VERSION 5.8 ;
BUSBITCHARS "[]" ;
DIVIDERCHAR "/" ;

SITE  CoreSite2
    CLASS       CORE ;
    SYMMETRY    Y ;
    SIZE        0.48 BY 7.56 ;
END  CoreSite2

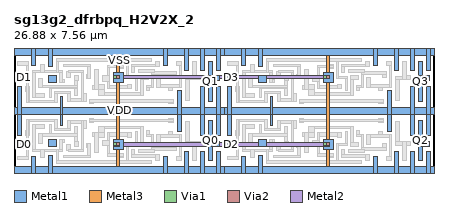
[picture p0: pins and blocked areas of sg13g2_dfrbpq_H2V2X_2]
MACRO sg13g2_dfrbpq_H2V2X_2
  CLASS CORE ;
  ORIGIN 0 0 ;
  FOREIGN sg13g2_dfrbpq_H2V2X_2 0 0 ;
  SIZE 26.880 BY 7.560 ;
  SYMMETRY X Y ;
  SITE CoreSite2 ;
  PIN D0
    DIRECTION INPUT ;
    USE SIGNAL ;
    ANTENNAMODEL OXIDE1 ;
    ANTENNAGATEAREA 0.1092 LAYER Metal1 ;
    PORT
      LAYER Metal1 ;
        RECT 0.255 1.375 0.610 1.855 ;
    END
  END D0
  PIN Q0
    DIRECTION OUTPUT ;
    USE SIGNAL ;
    ANTENNADIFFAREA 0.7161 LAYER Metal1 ;
    PORT
      LAYER Metal1 ;
        RECT 12.440 1.505 13.150 1.845 ;
        RECT 12.440 0.595 12.700 3.160 ;
    END
  END Q0
  PIN D1
    DIRECTION INPUT ;
    USE SIGNAL ;
    ANTENNAMODEL OXIDE1 ;
    ANTENNAGATEAREA 0.1092 LAYER Metal1 ;
    PORT
      LAYER Metal1 ;
        RECT 0.255 5.705 0.610 6.185 ;
    END
  END D1
  PIN Q1
    DIRECTION OUTPUT ;
    USE SIGNAL ;
    ANTENNADIFFAREA 0.7161 LAYER Metal1 ;
    PORT
      LAYER Metal1 ;
        RECT 12.440 4.400 12.700 6.965 ;
        RECT 12.440 5.715 13.150 6.055 ;
    END
  END Q1
  PIN D2
    DIRECTION INPUT ;
    USE SIGNAL ;
    ANTENNAMODEL OXIDE1 ;
    ANTENNAGATEAREA 0.1092 LAYER Metal1 ;
    PORT
      LAYER Metal1 ;
        RECT 13.695 1.375 14.050 1.855 ;
    END
  END D2
  PIN Q2
    DIRECTION OUTPUT ;
    USE SIGNAL ;
    ANTENNADIFFAREA 0.7161 LAYER Metal1 ;
    PORT
      LAYER Metal1 ;
        RECT 25.880 1.505 26.590 1.845 ;
        RECT 25.880 0.595 26.140 3.160 ;
    END
  END Q2
  PIN D3
    DIRECTION INPUT ;
    USE SIGNAL ;
    ANTENNAMODEL OXIDE1 ;
    ANTENNAGATEAREA 0.1092 LAYER Metal1 ;
    PORT
      LAYER Metal1 ;
        RECT 13.695 5.705 14.050 6.185 ;
    END
  END D3
  PIN Q3
    DIRECTION OUTPUT ;
    USE SIGNAL ;
    ANTENNADIFFAREA 0.7161 LAYER Metal1 ;
    PORT
      LAYER Metal1 ;
        RECT 25.880 4.400 26.140 6.965 ;
        RECT 25.880 5.715 26.590 6.055 ;
    END
  END Q3
  PIN VDD
    DIRECTION INOUT ;
    USE POWER ;
    SHAPE ABUTMENT ;
    NETEXPR "VDD VDD!" ;
    PORT
      LAYER Metal1 ;
        RECT 11.930 2.190 12.190 4.000 ;
        RECT 25.370 2.190 25.630 4.000 ;
        RECT 0.215 2.215 0.470 4.000 ;
        RECT 13.655 2.215 13.910 4.000 ;
        RECT 12.955 2.220 13.215 4.000 ;
        RECT 26.395 2.220 26.655 4.000 ;
        RECT 10.450 2.460 10.710 4.000 ;
        RECT 23.890 2.460 24.150 4.000 ;
        RECT 2.945 2.860 3.115 4.000 ;
        RECT 16.385 2.860 16.555 4.000 ;
        RECT 0.000 3.560 13.440 4.000 ;
        RECT 13.440 3.560 26.880 4.000 ;
        RECT 2.945 3.560 3.115 4.700 ;
        RECT 16.385 3.560 16.555 4.700 ;
        RECT 10.450 3.560 10.710 5.100 ;
        RECT 23.890 3.560 24.150 5.100 ;
        RECT 12.955 3.560 13.215 5.340 ;
        RECT 26.395 3.560 26.655 5.340 ;
        RECT 0.215 3.560 0.470 5.345 ;
        RECT 13.655 3.560 13.910 5.345 ;
        RECT 11.930 3.560 12.190 5.370 ;
        RECT 25.370 3.560 25.630 5.370 ;
    END
  END VDD
  PIN VSS
    DIRECTION INOUT ;
    USE GROUND ;
    SHAPE ABUTMENT ;
    NETEXPR "VSS VSS!" ;
    PORT
      LAYER Metal1 ;
        RECT 0.000 -0.220 13.440 0.220 ;
        RECT 13.440 -0.220 26.880 0.220 ;
        RECT 9.560 -0.220 9.820 0.885 ;
        RECT 1.140 -0.220 1.400 0.885 ;
        RECT 23.000 -0.220 23.260 0.885 ;
        RECT 14.580 -0.220 14.840 0.885 ;
        RECT 2.235 -0.220 2.495 0.915 ;
        RECT 15.675 -0.220 15.935 0.915 ;
        RECT 10.925 -0.220 11.160 1.190 ;
        RECT 24.365 -0.220 24.600 1.190 ;
        RECT 12.960 -0.220 13.215 1.200 ;
        RECT 11.935 -0.220 12.200 1.200 ;
        RECT 26.400 -0.220 26.655 1.200 ;
        RECT 25.375 -0.220 25.640 1.200 ;
    END
    PORT
      LAYER Metal1 ;
        RECT 12.960 6.360 13.215 7.780 ;
        RECT 11.935 6.360 12.200 7.780 ;
        RECT 26.400 6.360 26.655 7.780 ;
        RECT 25.375 6.360 25.640 7.780 ;
        RECT 10.925 6.370 11.160 7.780 ;
        RECT 24.365 6.370 24.600 7.780 ;
        RECT 2.235 6.645 2.495 7.780 ;
        RECT 15.675 6.645 15.935 7.780 ;
        RECT 9.560 6.675 9.820 7.780 ;
        RECT 1.140 6.675 1.400 7.780 ;
        RECT 23.000 6.675 23.260 7.780 ;
        RECT 14.580 6.675 14.840 7.780 ;
        RECT 0.000 7.340 13.440 7.780 ;
        RECT 13.440 7.340 26.880 7.780 ;
    END
  END VSS
  PIN CLK
    DIRECTION INPUT ;
    USE SIGNAL ;
    ANTENNAMODEL OXIDE1 ;
    ANTENNAGATEAREA 0.2418 LAYER Metal1 ;
    PORT
      LAYER Metal1 ;
        RECT 6.365 1.335 6.990 1.935 ;
        RECT 6.365 5.625 6.990 6.225 ;
        RECT 19.805 1.335 20.430 1.935 ;
        RECT 19.805 5.625 20.430 6.225 ;
      LAYER Metal3 ;
        RECT 6.580 0.200 6.780 7.360 ;
      LAYER Via1 ;
        RECT 6.365 1.540 6.555 1.730 ;
      LAYER Via2 ;
        RECT 6.580 1.540 6.770 1.730 ;
      LAYER Metal2 ;
        RECT 6.360 1.535 6.775 1.735 ;
      LAYER Via1 ;
        RECT 6.365 5.830 6.555 6.020 ;
      LAYER Via2 ;
        RECT 6.580 5.830 6.770 6.020 ;
      LAYER Metal2 ;
        RECT 6.360 5.825 6.775 6.025 ;
      LAYER Metal3 ;
        RECT 20.020 0.200 20.220 7.360 ;
      LAYER Via1 ;
        RECT 19.805 1.540 19.995 1.730 ;
      LAYER Via2 ;
        RECT 20.020 1.540 20.210 1.730 ;
      LAYER Metal2 ;
        RECT 19.800 1.535 20.215 1.735 ;
      LAYER Via1 ;
        RECT 19.805 5.830 19.995 6.020 ;
      LAYER Via2 ;
        RECT 20.020 5.830 20.210 6.020 ;
      LAYER Metal2 ;
        RECT 19.800 5.825 20.215 6.025 ;
        RECT 6.360 1.535 20.215 1.735 ;
        RECT 6.360 5.825 20.215 6.025 ;
    END
  END CLK
  PIN RESET_B
    DIRECTION INPUT ;
    USE SIGNAL ;
    ANTENNAPARTIALMETALAREA 0.905 LAYER Metal1 ;
    ANTENNAMODEL OXIDE1 ;
    ANTENNAGATEAREA 0.3276 LAYER Metal1 ;
    ANTENNAMAXAREACAR 2.762515 LAYER Metal1 ;
    PORT
      LAYER Metal1 ;
        RECT 2.200 1.510 2.750 1.965 ;
        RECT 15.640 1.510 16.190 1.965 ;
    END
    PORT
      LAYER Metal1 ;
        RECT 2.200 5.595 2.750 6.050 ;
        RECT 15.640 5.595 16.190 6.050 ;
    END
  END RESET_B
  OBS
    LAYER Metal1 ;
      RECT 10.990 1.555 11.250 3.105 ;
      RECT 10.990 1.555 11.920 1.795 ;
      RECT 11.410 1.540 11.920 1.795 ;
      RECT 11.410 0.590 11.670 1.795 ;
      RECT 9.910 2.100 10.170 2.495 ;
      RECT 9.130 2.100 10.730 2.260 ;
      RECT 10.570 0.625 10.730 2.260 ;
      RECT 9.130 1.655 9.385 2.260 ;
      RECT 10.380 0.625 10.730 0.885 ;
      RECT 8.455 2.125 8.660 2.500 ;
      RECT 8.455 2.125 8.950 2.295 ;
      RECT 8.790 1.145 8.950 2.295 ;
      RECT 10.165 1.275 10.390 1.665 ;
      RECT 8.790 1.275 10.390 1.465 ;
      RECT 7.960 1.145 8.970 1.315 ;
      RECT 9.910 3.025 10.180 3.285 ;
      RECT 4.855 3.025 5.115 3.285 ;
      RECT 4.855 3.075 10.180 3.235 ;
      RECT 7.510 0.805 7.680 1.310 ;
      RECT 7.510 0.805 9.310 0.965 ;
      RECT 9.050 0.625 9.310 0.965 ;
      RECT 1.200 2.640 1.940 2.900 ;
      RECT 1.200 1.170 1.360 2.900 ;
      RECT 7.745 1.555 7.935 2.450 ;
      RECT 2.935 1.755 3.215 1.965 ;
      RECT 2.935 1.170 3.095 1.965 ;
      RECT 7.170 1.555 7.935 1.725 ;
      RECT 7.170 0.440 7.330 1.725 ;
      RECT 1.200 1.170 3.095 1.330 ;
      RECT 2.705 0.440 2.875 1.330 ;
      RECT 1.720 0.815 1.980 1.330 ;
      RECT 8.540 0.440 8.800 0.625 ;
      RECT 2.705 0.440 8.800 0.605 ;
      RECT 5.425 2.630 8.275 2.790 ;
      RECT 8.115 1.510 8.275 2.790 ;
      RECT 5.425 2.060 5.785 2.790 ;
      RECT 5.020 2.150 5.785 2.410 ;
      RECT 5.155 2.060 5.785 2.410 ;
      RECT 5.155 1.135 5.415 2.410 ;
      RECT 8.115 1.510 8.600 1.770 ;
      RECT 5.965 2.145 7.525 2.370 ;
      RECT 7.265 2.075 7.525 2.370 ;
      RECT 5.965 0.855 6.125 2.370 ;
      RECT 5.650 1.540 6.125 1.870 ;
      RECT 6.755 0.810 6.990 1.070 ;
      RECT 5.965 0.855 6.990 1.025 ;
      RECT 4.630 1.440 4.895 1.700 ;
      RECT 4.685 1.300 4.895 1.700 ;
      RECT 4.685 0.785 4.865 1.700 ;
      RECT 3.165 0.785 4.865 0.960 ;
      RECT 0.790 3.080 2.765 3.240 ;
      RECT 2.605 2.520 2.765 3.240 ;
      RECT 3.455 2.985 4.625 3.145 ;
      RECT 4.290 2.685 4.625 3.145 ;
      RECT 0.790 2.240 0.980 3.240 ;
      RECT 3.455 2.520 3.615 3.145 ;
      RECT 4.290 1.170 4.450 3.145 ;
      RECT 2.605 2.520 3.615 2.680 ;
      RECT 0.720 2.240 0.980 2.520 ;
      RECT 0.790 0.645 0.950 3.240 ;
      RECT 3.385 1.225 3.645 1.640 ;
      RECT 3.465 1.170 4.450 1.330 ;
      RECT 0.210 0.645 0.950 0.840 ;
      RECT 2.245 2.145 2.425 2.900 ;
      RECT 3.890 1.510 4.075 2.805 ;
      RECT 2.245 2.145 4.075 2.315 ;
      RECT 1.585 2.145 4.075 2.305 ;
      RECT 1.585 1.705 1.845 2.305 ;
      RECT 3.890 1.510 4.110 1.810 ;
      RECT 10.990 4.455 11.250 6.005 ;
      RECT 10.990 5.765 11.920 6.005 ;
      RECT 11.410 5.765 11.920 6.020 ;
      RECT 11.410 5.765 11.670 6.970 ;
      RECT 9.910 5.065 10.170 5.460 ;
      RECT 9.130 5.300 10.730 5.460 ;
      RECT 10.570 5.300 10.730 6.935 ;
      RECT 9.130 5.300 9.385 5.905 ;
      RECT 10.380 6.675 10.730 6.935 ;
      RECT 8.455 5.060 8.660 5.435 ;
      RECT 8.455 5.265 8.950 5.435 ;
      RECT 8.790 5.265 8.950 6.415 ;
      RECT 10.165 5.895 10.390 6.285 ;
      RECT 8.790 6.095 10.390 6.285 ;
      RECT 7.960 6.245 8.970 6.415 ;
      RECT 9.910 4.275 10.180 4.535 ;
      RECT 4.855 4.275 5.115 4.535 ;
      RECT 4.855 4.325 10.180 4.485 ;
      RECT 7.510 6.250 7.680 6.755 ;
      RECT 7.510 6.595 9.310 6.755 ;
      RECT 9.050 6.595 9.310 6.935 ;
      RECT 1.200 4.660 1.940 4.920 ;
      RECT 1.200 4.660 1.360 6.390 ;
      RECT 7.745 5.110 7.935 6.005 ;
      RECT 2.935 5.595 3.215 5.805 ;
      RECT 2.935 5.595 3.095 6.390 ;
      RECT 7.170 5.835 7.935 6.005 ;
      RECT 7.170 5.835 7.330 7.120 ;
      RECT 1.200 6.230 3.095 6.390 ;
      RECT 2.705 6.230 2.875 7.120 ;
      RECT 1.720 6.230 1.980 6.745 ;
      RECT 8.540 6.935 8.800 7.120 ;
      RECT 2.705 6.955 8.800 7.120 ;
      RECT 5.425 4.770 8.275 4.930 ;
      RECT 8.115 4.770 8.275 6.050 ;
      RECT 5.425 4.770 5.785 5.500 ;
      RECT 5.020 5.150 5.785 5.410 ;
      RECT 5.155 5.150 5.785 5.500 ;
      RECT 5.155 5.150 5.415 6.425 ;
      RECT 8.115 5.790 8.600 6.050 ;
      RECT 5.965 5.190 7.525 5.415 ;
      RECT 7.265 5.190 7.525 5.485 ;
      RECT 5.965 5.190 6.125 6.705 ;
      RECT 5.650 5.690 6.125 6.020 ;
      RECT 6.755 6.490 6.990 6.750 ;
      RECT 5.965 6.535 6.990 6.705 ;
      RECT 4.630 5.860 4.895 6.120 ;
      RECT 4.685 5.860 4.895 6.260 ;
      RECT 4.685 5.860 4.865 6.775 ;
      RECT 3.165 6.600 4.865 6.775 ;
      RECT 0.790 4.320 2.765 4.480 ;
      RECT 2.605 4.320 2.765 5.040 ;
      RECT 3.455 4.415 4.625 4.575 ;
      RECT 4.290 4.415 4.625 4.875 ;
      RECT 0.790 4.320 0.980 5.320 ;
      RECT 3.455 4.415 3.615 5.040 ;
      RECT 4.290 4.415 4.450 6.390 ;
      RECT 2.605 4.880 3.615 5.040 ;
      RECT 0.720 5.040 0.980 5.320 ;
      RECT 0.790 4.320 0.950 6.915 ;
      RECT 3.385 5.920 3.645 6.335 ;
      RECT 3.465 6.230 4.450 6.390 ;
      RECT 0.210 6.720 0.950 6.915 ;
      RECT 2.245 4.660 2.425 5.415 ;
      RECT 3.890 4.755 4.075 6.050 ;
      RECT 2.245 5.245 4.075 5.415 ;
      RECT 1.585 5.255 4.075 5.415 ;
      RECT 1.585 5.255 1.845 5.855 ;
      RECT 3.890 5.750 4.110 6.050 ;
      RECT 24.430 1.555 24.690 3.105 ;
      RECT 24.430 1.555 25.360 1.795 ;
      RECT 24.850 1.540 25.360 1.795 ;
      RECT 24.850 0.590 25.110 1.795 ;
      RECT 23.350 2.100 23.610 2.495 ;
      RECT 22.570 2.100 24.170 2.260 ;
      RECT 24.010 0.625 24.170 2.260 ;
      RECT 22.570 1.655 22.825 2.260 ;
      RECT 23.820 0.625 24.170 0.885 ;
      RECT 21.895 2.125 22.100 2.500 ;
      RECT 21.895 2.125 22.390 2.295 ;
      RECT 22.230 1.145 22.390 2.295 ;
      RECT 23.605 1.275 23.830 1.665 ;
      RECT 22.230 1.275 23.830 1.465 ;
      RECT 21.400 1.145 22.410 1.315 ;
      RECT 23.350 3.025 23.620 3.285 ;
      RECT 18.295 3.025 18.555 3.285 ;
      RECT 18.295 3.075 23.620 3.235 ;
      RECT 20.950 0.805 21.120 1.310 ;
      RECT 20.950 0.805 22.750 0.965 ;
      RECT 22.490 0.625 22.750 0.965 ;
      RECT 14.640 2.640 15.380 2.900 ;
      RECT 14.640 1.170 14.800 2.900 ;
      RECT 21.185 1.555 21.375 2.450 ;
      RECT 16.375 1.755 16.655 1.965 ;
      RECT 16.375 1.170 16.535 1.965 ;
      RECT 20.610 1.555 21.375 1.725 ;
      RECT 20.610 0.440 20.770 1.725 ;
      RECT 14.640 1.170 16.535 1.330 ;
      RECT 16.145 0.440 16.315 1.330 ;
      RECT 15.160 0.815 15.420 1.330 ;
      RECT 21.980 0.440 22.240 0.625 ;
      RECT 16.145 0.440 22.240 0.605 ;
      RECT 18.865 2.630 21.715 2.790 ;
      RECT 21.555 1.510 21.715 2.790 ;
      RECT 18.865 2.060 19.225 2.790 ;
      RECT 18.460 2.150 19.225 2.410 ;
      RECT 18.595 2.060 19.225 2.410 ;
      RECT 18.595 1.135 18.855 2.410 ;
      RECT 21.555 1.510 22.040 1.770 ;
      RECT 19.405 2.145 20.965 2.370 ;
      RECT 20.705 2.075 20.965 2.370 ;
      RECT 19.405 0.855 19.565 2.370 ;
      RECT 19.090 1.540 19.565 1.870 ;
      RECT 20.195 0.810 20.430 1.070 ;
      RECT 19.405 0.855 20.430 1.025 ;
      RECT 18.070 1.440 18.335 1.700 ;
      RECT 18.125 1.300 18.335 1.700 ;
      RECT 18.125 0.785 18.305 1.700 ;
      RECT 16.605 0.785 18.305 0.960 ;
      RECT 14.230 3.080 16.205 3.240 ;
      RECT 16.045 2.520 16.205 3.240 ;
      RECT 16.895 2.985 18.065 3.145 ;
      RECT 17.730 2.685 18.065 3.145 ;
      RECT 14.230 2.240 14.420 3.240 ;
      RECT 16.895 2.520 17.055 3.145 ;
      RECT 17.730 1.170 17.890 3.145 ;
      RECT 16.045 2.520 17.055 2.680 ;
      RECT 14.160 2.240 14.420 2.520 ;
      RECT 14.230 0.645 14.390 3.240 ;
      RECT 16.825 1.225 17.085 1.640 ;
      RECT 16.905 1.170 17.890 1.330 ;
      RECT 13.650 0.645 14.390 0.840 ;
      RECT 15.685 2.145 15.865 2.900 ;
      RECT 17.330 1.510 17.515 2.805 ;
      RECT 15.685 2.145 17.515 2.315 ;
      RECT 15.025 2.145 17.515 2.305 ;
      RECT 15.025 1.705 15.285 2.305 ;
      RECT 17.330 1.510 17.550 1.810 ;
      RECT 24.430 4.455 24.690 6.005 ;
      RECT 24.430 5.765 25.360 6.005 ;
      RECT 24.850 5.765 25.360 6.020 ;
      RECT 24.850 5.765 25.110 6.970 ;
      RECT 23.350 5.065 23.610 5.460 ;
      RECT 22.570 5.300 24.170 5.460 ;
      RECT 24.010 5.300 24.170 6.935 ;
      RECT 22.570 5.300 22.825 5.905 ;
      RECT 23.820 6.675 24.170 6.935 ;
      RECT 21.895 5.060 22.100 5.435 ;
      RECT 21.895 5.265 22.390 5.435 ;
      RECT 22.230 5.265 22.390 6.415 ;
      RECT 23.605 5.895 23.830 6.285 ;
      RECT 22.230 6.095 23.830 6.285 ;
      RECT 21.400 6.245 22.410 6.415 ;
      RECT 23.350 4.275 23.620 4.535 ;
      RECT 18.295 4.275 18.555 4.535 ;
      RECT 18.295 4.325 23.620 4.485 ;
      RECT 20.950 6.250 21.120 6.755 ;
      RECT 20.950 6.595 22.750 6.755 ;
      RECT 22.490 6.595 22.750 6.935 ;
      RECT 14.640 4.660 15.380 4.920 ;
      RECT 14.640 4.660 14.800 6.390 ;
      RECT 21.185 5.110 21.375 6.005 ;
      RECT 16.375 5.595 16.655 5.805 ;
      RECT 16.375 5.595 16.535 6.390 ;
      RECT 20.610 5.835 21.375 6.005 ;
      RECT 20.610 5.835 20.770 7.120 ;
      RECT 14.640 6.230 16.535 6.390 ;
      RECT 16.145 6.230 16.315 7.120 ;
      RECT 15.160 6.230 15.420 6.745 ;
      RECT 21.980 6.935 22.240 7.120 ;
      RECT 16.145 6.955 22.240 7.120 ;
      RECT 18.865 4.770 21.715 4.930 ;
      RECT 21.555 4.770 21.715 6.050 ;
      RECT 18.865 4.770 19.225 5.500 ;
      RECT 18.460 5.150 19.225 5.410 ;
      RECT 18.595 5.150 19.225 5.500 ;
      RECT 18.595 5.150 18.855 6.425 ;
      RECT 21.555 5.790 22.040 6.050 ;
      RECT 19.405 5.190 20.965 5.415 ;
      RECT 20.705 5.190 20.965 5.485 ;
      RECT 19.405 5.190 19.565 6.705 ;
      RECT 19.090 5.690 19.565 6.020 ;
      RECT 20.195 6.490 20.430 6.750 ;
      RECT 19.405 6.535 20.430 6.705 ;
      RECT 18.070 5.860 18.335 6.120 ;
      RECT 18.125 5.860 18.335 6.260 ;
      RECT 18.125 5.860 18.305 6.775 ;
      RECT 16.605 6.600 18.305 6.775 ;
      RECT 14.230 4.320 16.205 4.480 ;
      RECT 16.045 4.320 16.205 5.040 ;
      RECT 16.895 4.415 18.065 4.575 ;
      RECT 17.730 4.415 18.065 4.875 ;
      RECT 14.230 4.320 14.420 5.320 ;
      RECT 16.895 4.415 17.055 5.040 ;
      RECT 17.730 4.415 17.890 6.390 ;
      RECT 16.045 4.880 17.055 5.040 ;
      RECT 14.160 5.040 14.420 5.320 ;
      RECT 14.230 4.320 14.390 6.915 ;
      RECT 16.825 5.920 17.085 6.335 ;
      RECT 16.905 6.230 17.890 6.390 ;
      RECT 13.650 6.720 14.390 6.915 ;
      RECT 15.685 4.660 15.865 5.415 ;
      RECT 17.330 4.755 17.515 6.050 ;
      RECT 15.685 5.245 17.515 5.415 ;
      RECT 15.025 5.255 17.515 5.415 ;
      RECT 15.025 5.255 15.285 5.855 ;
      RECT 17.330 5.750 17.550 6.050 ;
  END
END sg13g2_dfrbpq_H2V2X_2

END LIBRARY
